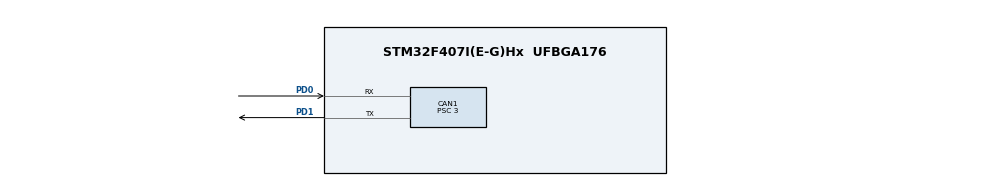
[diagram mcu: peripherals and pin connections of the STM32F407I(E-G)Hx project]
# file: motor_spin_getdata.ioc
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CAN1.BS1=CAN_BS1_9TQ
CAN1.BS2=CAN_BS2_4TQ
CAN1.CalculateBaudRate=1000000
CAN1.CalculateTimeBit=1000
CAN1.CalculateTimeQuantum=71.42857142857143
CAN1.Mode=CAN_MODE_NORMAL
CAN1.Prescaler=3
Mcu.Family=STM32F4
Mcu.Name=STM32F407I(E-G)Hx
Mcu.Package=UFBGA176
NVIC.CAN1_RX0_IRQn=true\:0\:0\:false\:false\:true\:true\:true\:true
NVIC.PriorityGroup=NVIC_PRIORITYGROUP_4
PD0.Mode=CAN_Activate
PD0.Signal=CAN1_RX
PD1.Mode=CAN_Activate
PD1.Signal=CAN1_TX
PH0-OSC_IN.Mode=HSE-External-Oscillator
PH0-OSC_IN.Signal=RCC_OSC_IN
PH1-OSC_OUT.Mode=HSE-External-Oscillator
PH1-OSC_OUT.Signal=RCC_OSC_OUT
ProjectManager.HeapSize=0x200
ProjectManager.StackSize=0x400
ProjectManager.TargetToolchain=STM32CubeIDE
RCC.48MHZClocksFreq_Value=42000000
RCC.AHBFreq_Value=84000000
RCC.APB1CLKDivider=RCC_HCLK_DIV2
RCC.APB1Freq_Value=42000000
RCC.APB1TimFreq_Value=84000000
RCC.APB2Freq_Value=84000000
RCC.APB2TimFreq_Value=84000000
RCC.CortexFreq_Value=84000000
RCC.HCLKFreq_Value=84000000
RCC.HSE_VALUE=12000000
RCC.HSI_VALUE=16000000
RCC.LSE_VALUE=32768
RCC.PLLM=6
RCC.PLLN=84
RCC.PLLSourceVirtual=RCC_PLLSOURCE_HSE
RCC.SYSCLKFreq_VALUE=84000000
RCC.SYSCLKSource=RCC_SYSCLKSOURCE_PLLCLK
RCC.VCOOutputFreq_Value=168000000
board=custom

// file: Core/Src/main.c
/* USER CODE BEGIN Header */
/**
  ******************************************************************************
  * @file           : main.c
  * @brief          : Main program body
  ******************************************************************************
  * @attention
  *
  * Copyright (c) 2023 STMicroelectronics.
  * All rights reserved.
  *
  * This software is licensed under terms that can be found in the LICENSE file
  * in the root directory of this software component.
  * If no LICENSE file comes with this software, it is provided AS-IS.
  *
  ******************************************************************************
  */
/* USER CODE END Header */
#include "main.h"

/* USER CODE BEGIN PM */
int16_t motor_rpm1;
int16_t motor_rpm2;
int16_t motor_rpm3;
float motor_rpm4;
int16_t motor_rpm5;
int16_t motor_rpm6;
int16_t x;
uint16_t y;

#define P_MIN -95.5f    // Radians
#define P_MAX 95.5f
#define V_MIN -45.0f    // Rad/s
#define V_MAX 45.0f
#define KP_MIN 0.0f     // N-m/rad
#define KP_MAX 500.0f
#define KD_MIN 0.0f     // N-m/rad/s
#define KD_MAX 5.0f
#define T_MIN -18.0f
#define T_MAX 18.0f

/* USER CODE END PM */

CAN_HandleTypeDef hcan1;

void SystemClock_Config(void);
static void MX_GPIO_Init(void);
static void MX_CAN1_Init(void);

/* USER CODE BEGIN 0 */

static uint16_t float_to_uint(float x, float x_min, float x_max, uint8_t bits)
{
    float span = x_max - x_min;
    float offset = x_min;

    return (uint16_t) ((x-offset)*((float)((1<<bits)-1))/span);
}

static float uint_to_float(int x_int, float x_min, float x_max, int bits)
{
    float span = x_max - x_min;
    float offset = x_min;
    return ((float)x_int)*span/((float)((1<<bits)-1)) + offset;
}

void setup_can(){
 CAN_FilterTypeDef can_filter_st = {0};
 can_filter_st.FilterActivation = ENABLE;
 can_filter_st.FilterMode = CAN_FILTERMODE_IDMASK;
 can_filter_st.FilterScale = CAN_FILTERSCALE_32BIT;
 can_filter_st.FilterIdHigh = 0;
 can_filter_st.FilterIdLow = 0;
 can_filter_st.FilterMaskIdHigh = 0;
 can_filter_st.FilterMaskIdLow = 0;
 can_filter_st.FilterBank=0;
 can_filter_st.FilterFIFOAssignment = CAN_RX_FIFO0;
 HAL_CAN_ConfigFilter(&hcan1, &can_filter_st);
 HAL_CAN_Start(&hcan1);
 HAL_CAN_ActivateNotification(&hcan1,CAN_IT_RX_FIFO0_MSG_PENDING | CAN_IT_RX_FIFO0_FULL| CAN_IT_RX_FIFO0_OVERRUN);
}

void HAL_CAN_RxFifo0MsgPendingCallback(CAN_HandleTypeDef *hcan){
CAN_RxHeaderTypeDef rx_header;
uint8_t rx_buffer[8];
HAL_CAN_DeactivateNotification(hcan,
  CAN_IT_RX_FIFO0_MSG_PENDING | CAN_IT_RX_FIFO0_FULL| CAN_IT_RX_FIFO0_OVERRUN);
HAL_CAN_GetRxMessage(hcan, CAN_RX_FIFO0, &rx_header, rx_buffer);

//M3508 motors
//if (rx_header.StdId == 0x201)
//{
//	motor_rpm1 = (rx_buffer[2] << 8) + rx_buffer[3];
//}

//if (rx_header.StdId == 0x202)
//{
//	motor_rpm2 = (rx_buffer[2] << 8) + rx_buffer[3];
//}

// GM6020 Motors
//if (rx_header.StdId == 0x205)
//{
//	motor_rpm3 = (rx_buffer[2] << 8) + rx_buffer[3];
//}
if (rx_buffer[0] == 0x02)
{
	motor_rpm4 = uint_to_float(((rx_buffer[1] << 8 ) | (rx_buffer[2])),P_MIN,P_MAX,16);
}
//if (rx_header.StdId == 0x207)
//{
//	motor_rpm5 = (rx_buffer[2] << 8) + rx_buffer[3];
//}
//if (rx_header.StdId == 0x208)
//{
//	motor_rpm6 = (rx_buffer[2] << 8) + rx_buffer[3];
//}

HAL_CAN_ActivateNotification(hcan,
  CAN_IT_RX_FIFO0_MSG_PENDING | CAN_IT_RX_FIFO0_FULL| CAN_IT_RX_FIFO0_OVERRUN);
}

void ctrl_motor(int16_t torque1,int16_t torque2){
 uint8_t tx_msg[8];
 CAN_TxHeaderTypeDef CAN_tx_message;
 uint32_t send_mail_box;
 CAN_tx_message.IDE = CAN_ID_STD;
 CAN_tx_message.RTR = CAN_RTR_DATA;
 CAN_tx_message.DLC = 0x08;
 CAN_tx_message.StdId = 0x200;
 tx_msg[0] = torque1>>8;
 tx_msg[1] = torque1;
 tx_msg[2] = torque2>>8;
 tx_msg[3] = torque2;
 HAL_CAN_AddTxMessage(&hcan1, &CAN_tx_message, tx_msg, &send_mail_box);
}

void ctrl_GM_motor(int16_t torque1,int16_t torque2,int16_t torque3,int16_t torque4){
 uint8_t tx_msg[8];
 CAN_TxHeaderTypeDef CAN_tx_message;
 uint32_t send_mail_box;
 CAN_tx_message.IDE = CAN_ID_STD;
 CAN_tx_message.RTR = CAN_RTR_DATA;
 CAN_tx_message.DLC = 0x08;
 CAN_tx_message.StdId = 0x1FF;
 tx_msg[0] = torque1>>8;
 tx_msg[1] = torque1;
 tx_msg[2] = torque2>>8;
 tx_msg[3] = torque2;
 tx_msg[4] = torque3>>8;
 tx_msg[5] = torque3;
 tx_msg[6] = torque4>>8;
 tx_msg[7] = torque4;
 HAL_CAN_AddTxMessage(&hcan1, &CAN_tx_message, tx_msg, &send_mail_box);
}

uint8_t p;
uint8_t v;
uint8_t kp;
uint8_t kd;
uint8_t t;

void ctrl_2_new_motor(float f_p, float f_v, float f_kp, float f_kd, float f_t){
 uint8_t buf[8];
 CAN_TxHeaderTypeDef CAN_tx_message;
 uint32_t send_mail_box;
 CAN_tx_message.IDE = CAN_ID_STD;
 CAN_tx_message.RTR = CAN_RTR_DATA;
 CAN_tx_message.DLC = 0x08;
 CAN_tx_message.StdId = 0x02;

 p = float_to_uint(f_p,      P_MIN,  P_MAX,  16);
 v = float_to_uint(f_v,      V_MIN,  V_MAX,  12);
 kp = float_to_uint(f_kp,    KP_MIN, KP_MAX, 12);
 kd = float_to_uint(f_kd,    KD_MIN, KD_MAX, 12);
 t = float_to_uint(f_t,      T_MIN,  T_MAX,  12);

 buf[0] = p>>8;
 buf[1] = p&0xFF;
 buf[2] = v>>4;
 buf[3] = ((v&0xF)<<4)|(kp>>8);
 buf[4] = kp&0xFF;
 buf[5] = kd>>4;
 buf[6] = ((kd&0xF)<<4)|(t>>8);
 buf[7] = t&0xff;
 HAL_CAN_AddTxMessage(&hcan1, &CAN_tx_message, buf, &send_mail_box);
}
void ctrl_1_new_motor(void){
 uint8_t tx_msg[8];
 CAN_TxHeaderTypeDef CAN_tx_message;
 uint32_t send_mail_box;
 CAN_tx_message.IDE = CAN_ID_STD;
 CAN_tx_message.RTR = CAN_RTR_DATA;
 CAN_tx_message.DLC = 0x08;
 CAN_tx_message.StdId = 0x02;
 tx_msg[0] = 0xFF;
 tx_msg[1] = 0xFF;
 tx_msg[2] = 0xFF;
 tx_msg[3] = 0xFF;
 tx_msg[4] = 0xFF;
 tx_msg[5] = 0xFF;
 tx_msg[6] = 0xFF;
 tx_msg[7] = 0xFC;
 HAL_CAN_AddTxMessage(&hcan1, &CAN_tx_message, tx_msg, &send_mail_box);
}

/* USER CODE END 0 */

int main(void)
{

  /* MCU Configuration--------------------------------------------------------*/

  /* Reset of all peripherals, Initializes the Flash interface and the Systick. */
  HAL_Init();

  /* Configure the system clock */
  SystemClock_Config();

  /* Initialize all configured peripherals */
  MX_GPIO_Init();
  MX_CAN1_Init();
  /* USER CODE BEGIN 2 */
  setup_can();
  ctrl_1_new_motor();

  //uint32_t last_button_time = HAL_GetTick();
  //int16_t spd = 1;
  /* USER CODE END 2 */

  /* Infinite loop */
  /* USER CODE BEGIN WHILE */
  while (1)
  {

//	  ctrl_motor(pid_lol(SPEED,motor_rpm1) , pid_lol_2(SPEED,motor_rpm2));
//	  ctrl_1_GM_motor(pid_lol(SPEED,motor_rpm1));
//	  ctrl_GM_motor(pid_lol(SPEED,motor_rpm3), pid_lol_2(SPEED,motor_rpm4), pid_lol_3(SPEED,motor_rpm5), pid_lol_4(SPEED,motor_rpm6));
	  //ctrl_motor(pid_lol(SPEED,motor_rpm1) , pid_lol(SPEED,motor_rpm2));
	  //ctrl_motor(SPEED);
//	  ctrl_2_new_motor(10,0,0,0,0);
	  HAL_Delay(1);

	  /*
	  if (HAL_GPIO_ReadPin(GPIOA, GPIO_PIN_0) == 0){
		  if (HAL_GetTick() - last_button_time > 500){
			  spd = (spd == 1) ? 0 : (spd== 0) ? -1 : (spd == -1) ? 1 : 0;
			  last_button_time = HAL_GetTick();
		  }
	  }
	  */

    /* USER CODE END WHILE */

  }
}

void SystemClock_Config(void)
{
  RCC_OscInitTypeDef RCC_OscInitStruct = {0};
  RCC_ClkInitTypeDef RCC_ClkInitStruct = {0};

  /** Configure the main internal regulator output voltage
  */
  __HAL_RCC_PWR_CLK_ENABLE();
  __HAL_PWR_VOLTAGESCALING_CONFIG(PWR_REGULATOR_VOLTAGE_SCALE1);

  /** Initializes the RCC Oscillators according to the specified parameters
  * in the RCC_OscInitTypeDef structure.
  */
  RCC_OscInitStruct.OscillatorType = RCC_OSCILLATORTYPE_HSE;
  RCC_OscInitStruct.HSEState = RCC_HSE_ON;
  RCC_OscInitStruct.PLL.PLLState = RCC_PLL_ON;
  RCC_OscInitStruct.PLL.PLLSource = RCC_PLLSOURCE_HSE;
  RCC_OscInitStruct.PLL.PLLM = 6;
  RCC_OscInitStruct.PLL.PLLN = 168;
  RCC_OscInitStruct.PLL.PLLP = RCC_PLLP_DIV2;
  RCC_OscInitStruct.PLL.PLLQ = 4;
  if (HAL_RCC_OscConfig(&RCC_OscInitStruct) != HAL_OK)
  {
    Error_Handler();
  }

  /** Initializes the CPU, AHB and APB buses clocks
  */
  RCC_ClkInitStruct.ClockType = RCC_CLOCKTYPE_HCLK|RCC_CLOCKTYPE_SYSCLK
                              |RCC_CLOCKTYPE_PCLK1|RCC_CLOCKTYPE_PCLK2;
  RCC_ClkInitStruct.SYSCLKSource = RCC_SYSCLKSOURCE_PLLCLK;
  RCC_ClkInitStruct.AHBCLKDivider = RCC_SYSCLK_DIV1;
  RCC_ClkInitStruct.APB1CLKDivider = RCC_HCLK_DIV4;
  RCC_ClkInitStruct.APB2CLKDivider = RCC_HCLK_DIV2;

  if (HAL_RCC_ClockConfig(&RCC_ClkInitStruct, FLASH_LATENCY_5) != HAL_OK)
  {
    Error_Handler();
  }
}

static void MX_CAN1_Init(void)
{

  hcan1.Instance = CAN1;
  hcan1.Init.Prescaler = 3;
  hcan1.Init.Mode = CAN_MODE_NORMAL;
  hcan1.Init.SyncJumpWidth = CAN_SJW_1TQ;
  hcan1.Init.TimeSeg1 = CAN_BS1_9TQ;
  hcan1.Init.TimeSeg2 = CAN_BS2_4TQ;
  hcan1.Init.TimeTriggeredMode = DISABLE;
  hcan1.Init.AutoBusOff = DISABLE;
  hcan1.Init.AutoWakeUp = DISABLE;
  hcan1.Init.AutoRetransmission = DISABLE;
  hcan1.Init.ReceiveFifoLocked = DISABLE;
  hcan1.Init.TransmitFifoPriority = DISABLE;
  if (HAL_CAN_Init(&hcan1) != HAL_OK)
  {
    Error_Handler();
  }

}

static void MX_GPIO_Init(void)
{

  /* GPIO Ports Clock Enable */

  __HAL_RCC_GPIOD_CLK_ENABLE();
  __HAL_RCC_GPIOH_CLK_ENABLE();

}

void Error_Handler(void)
{
  __disable_irq();
  while (1)
  {
  }
}
